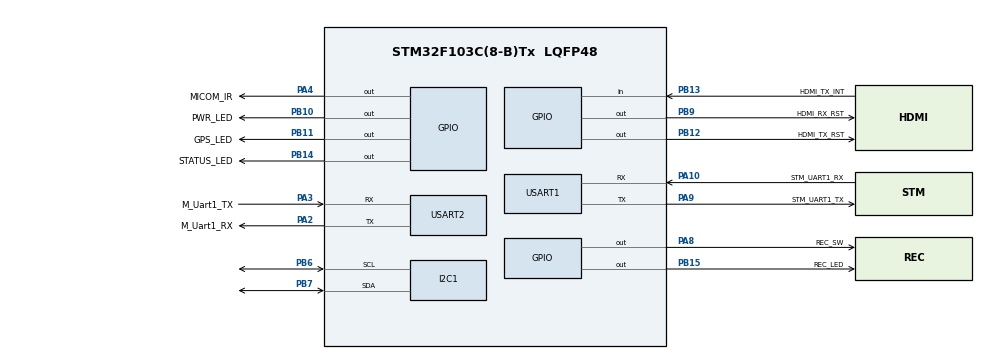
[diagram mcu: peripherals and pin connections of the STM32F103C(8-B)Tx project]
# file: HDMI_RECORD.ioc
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Mcu.Family=STM32F1
Mcu.Name=STM32F103C(8-B)Tx
Mcu.Package=LQFP48
NVIC.PriorityGroup=NVIC_PRIORITYGROUP_4
PA10.GPIO_Label=STM_UART1_RX
PA10.GPIO_PuPd=GPIO_PULLUP
PA10.Mode=Asynchronous
PA10.Signal=USART1_RX
PA2.GPIO_Label=M_Uart1_RX
PA2.Mode=Asynchronous
PA2.Signal=USART2_TX
PA3.GPIO_Label=M_Uart1_TX
PA3.GPIO_PuPd=GPIO_PULLUP
PA3.Mode=Asynchronous
PA3.Signal=USART2_RX
PA4.GPIO_Label=MICOM_IR
PA4.Signal=GPIO_Output
PA8.GPIO_Label=REC_SW
PA8.Signal=GPIO_Output
PA9.GPIO_Label=STM_UART1_TX
PA9.Mode=Asynchronous
PA9.Signal=USART1_TX
PB10.GPIO_Label=PWR_LED
PB10.Signal=GPIO_Output
PB11.GPIO_Label=GPS_LED
PB11.Signal=GPIO_Output
PB12.GPIO_Label=HDMI_TX_RST
PB12.Signal=GPIO_Output
PB13.GPIO_Label=HDMI_TX_INT
PB13.Signal=GPIO_Input
PB14.GPIO_Label=STATUS_LED
PB14.Signal=GPIO_Output
PB15.GPIO_Label=REC_LED
PB15.Signal=GPIO_Output
PB6.Mode=I2C
PB6.Signal=I2C1_SCL
PB7.Mode=I2C
PB7.Signal=I2C1_SDA
PB9.GPIO_Label=HDMI_RX_RST
PB9.Signal=GPIO_Output
ProjectManager.HeapSize=0x200
ProjectManager.StackSize=0x400
ProjectManager.TargetToolchain=STM32CubeIDE
RCC.APB1Freq_Value=8000000
RCC.APB2Freq_Value=8000000
USART1.VirtualMode=VM_ASYNC
USART2.VirtualMode=VM_ASYNC
VP_SYS_VS_ND.Mode=No_Debug
board=custom

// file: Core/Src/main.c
/* USER CODE BEGIN Header */
/**
  ******************************************************************************
  * @file           : main.c
  * @brief          : Main program body
  ******************************************************************************
  * @attention
  *
  * Copyright (c) 2026 STMicroelectronics.
  * All rights reserved.
  *
  * This software is licensed under terms that can be found in the LICENSE file
  * in the root directory of this software component.
  * If no LICENSE file comes with this software, it is provided AS-IS.
  *
  ******************************************************************************
  */
/* USER CODE END Header */
#include "main.h"
#include "stdio.h"
//#include "IT68013CX\it68013CX_main.c" //yjh2026

I2C_HandleTypeDef hi2c1;

UART_HandleTypeDef huart1;
UART_HandleTypeDef huart2;
volatile unsigned int ite_int_check = 0; //oec20251221

void SystemClock_Config(void);
static void MX_GPIO_Init(void);
static void MX_I2C1_Init(void);
static void MX_USART1_UART_Init(void);
static void MX_USART2_UART_Init(void);

/* USER CODE BEGIN 0 */

#if 1	//oec20240609

typedef enum tagHDMI_Video_Type {
    HDMI_Unkown = 0 ,
    HDMI_640x480p60 = 1 ,
    HDMI_480p60,
    HDMI_480p60_16x9,
    HDMI_720p60,
    HDMI_1080i60,
    HDMI_480i60,
    HDMI_480i60_16x9,
    HDMI_1080p60 = 16,
    HDMI_576p50,
    HDMI_576p50_16x9,
    HDMI_720p50,
    HDMI_1080i50,
    HDMI_576i50,
    HDMI_576i50_16x9,
    HDMI_1080p50 = 31,
    HDMI_1080p24,
    HDMI_1080p25,
    HDMI_1080p30,
    HDMI_720p30 = 61,
    HDMI_4k24 =93,
    HDMI_4k25 = 94,
    HDMI_4k30 = 95,
    HDMI_4k24_SMPTE = 98,
} HDMI_Video_Type ;

typedef enum tagHDMI_OutputColorMode {
    HDMI_RGB444,
    HDMI_YUV422,/*20230111*/
    HDMI_YUV444
} HDMI_OutputColorMode ;

typedef unsigned char u8;

#endif

#if 1
int _write(int file, char* p, int len){
	HAL_UART_Transmit(&huart1, (unsigned char*)p, len, 10);
	return len;
}
#endif
void Reset_ITE(void)
{
  printf("#####ITE Reset!!\r\n");
	HAL_Delay(100);
	//yjh2026 회로도 확인해서 수정, PA5(MCU_RESET)은 ITE칩 리셋이 아님
	HAL_GPIO_WritePin(HDMI_RX_RST_GPIO_Port, HDMI_RX_RST_Pin, GPIO_PIN_RESET); //yjh2026 PB9
	HAL_GPIO_WritePin(HDMI_TX_RST_GPIO_Port, HDMI_TX_RST_Pin, GPIO_PIN_RESET); //yjh2026 PB12
	HAL_Delay(100);
	HAL_GPIO_WritePin(HDMI_RX_RST_GPIO_Port, HDMI_RX_RST_Pin, GPIO_PIN_SET); //yjh2026
	HAL_GPIO_WritePin(HDMI_TX_RST_GPIO_Port, HDMI_TX_RST_Pin, GPIO_PIN_SET); //yjh2026
	HAL_Delay(10); //yjh2026 TODO - 리셋후 대기시간 데이터시트 확인
}

void LED_ON_OFF(u8 onoff)
{
	// HAL_GPIO_WritePin(GPIOA, GPIO_PIN_1, onoff);
//  HAL_GPIO_WritePin(GPIOA, UV_LED_ON_Pin, onoff);

	#if 0
	printf("!!!!LED STATUS %d\r\n",onoff);
	printf("!!!!LED STATUS %d\r\n",onoff);
	printf("!!!!LED STATUS %d\r\n",onoff);
	printf("!!!!LED STATUS %d\r\n",onoff);
	#endif
}

void HAL_GPIO_EXTI_Callback(uint16_t GPIO_Pin) {  //oec20251221
	//yjh2026 TODO - .ioc에서 PB13 EXTI로 바꿔야함
	//yjh2026 TODO - RX_INT 미연결이라 RX쪽은 polling으로 처리
	if (GPIO_Pin == HDMI_TX_INT_Pin) { //yjh2026 PB4->PB13 회로도 확인
		if (HAL_GPIO_ReadPin(HDMI_TX_INT_GPIO_Port, HDMI_TX_INT_Pin) == GPIO_PIN_SET) {
			ite_int_check = 1;
			printf("########HDMI TX Interrupt Detected!!\r\n");
		}
	}
}

/* USER CODE END 0 */

int main(void)
{

  /* MCU Configuration--------------------------------------------------------*/

  /* Reset of all peripherals, Initializes the Flash interface and the Systick. */
  HAL_Init();

  /* Configure the system clock */
  SystemClock_Config();

  /* Initialize all configured peripherals */
  MX_GPIO_Init();
  MX_I2C1_Init();
  MX_USART1_UART_Init();
  MX_USART2_UART_Init();

  /* Infinite loop */
  Reset_ITE();

  /* USER CODE BEGIN WHILE */
  while (1)
  {
    extern 	void OEM_1_MainLoop(void);
    extern   void it68013CX_main(void);
	  OEM_1_MainLoop();  //HDMI TX
    it68013CX_main();    //HDMI RX

    /* USER CODE END WHILE */

  }
}

void SystemClock_Config(void)
{
  RCC_OscInitTypeDef RCC_OscInitStruct = {0};
  RCC_ClkInitTypeDef RCC_ClkInitStruct = {0};

  /** Initializes the RCC Oscillators according to the specified parameters
  * in the RCC_OscInitTypeDef structure.
  */
  RCC_OscInitStruct.OscillatorType = RCC_OSCILLATORTYPE_HSI;
  RCC_OscInitStruct.HSIState = RCC_HSI_ON;
  RCC_OscInitStruct.HSICalibrationValue = RCC_HSICALIBRATION_DEFAULT;
  RCC_OscInitStruct.PLL.PLLState = RCC_PLL_NONE;
  if (HAL_RCC_OscConfig(&RCC_OscInitStruct) != HAL_OK)
  {
    Error_Handler();
  }

  /** Initializes the CPU, AHB and APB buses clocks
  */
  RCC_ClkInitStruct.ClockType = RCC_CLOCKTYPE_HCLK|RCC_CLOCKTYPE_SYSCLK
                              |RCC_CLOCKTYPE_PCLK1|RCC_CLOCKTYPE_PCLK2;
  RCC_ClkInitStruct.SYSCLKSource = RCC_SYSCLKSOURCE_HSI;
  RCC_ClkInitStruct.AHBCLKDivider = RCC_SYSCLK_DIV1;
  RCC_ClkInitStruct.APB1CLKDivider = RCC_HCLK_DIV1;
  RCC_ClkInitStruct.APB2CLKDivider = RCC_HCLK_DIV1;

  if (HAL_RCC_ClockConfig(&RCC_ClkInitStruct, FLASH_LATENCY_0) != HAL_OK)
  {
    Error_Handler();
  }
}

static void MX_I2C1_Init(void)
{

  hi2c1.Instance = I2C1;
  hi2c1.Init.ClockSpeed = 100000;
  hi2c1.Init.DutyCycle = I2C_DUTYCYCLE_2;
  hi2c1.Init.OwnAddress1 = 0;
  hi2c1.Init.AddressingMode = I2C_ADDRESSINGMODE_7BIT;
  hi2c1.Init.DualAddressMode = I2C_DUALADDRESS_DISABLE;
  hi2c1.Init.OwnAddress2 = 0;
  hi2c1.Init.GeneralCallMode = I2C_GENERALCALL_DISABLE;
  hi2c1.Init.NoStretchMode = I2C_NOSTRETCH_DISABLE;
  if (HAL_I2C_Init(&hi2c1) != HAL_OK)
  {
    Error_Handler();
  }

}

static void MX_USART1_UART_Init(void)
{

  huart1.Instance = USART1;
  huart1.Init.BaudRate = 115200;
  huart1.Init.WordLength = UART_WORDLENGTH_8B;
  huart1.Init.StopBits = UART_STOPBITS_1;
  huart1.Init.Parity = UART_PARITY_NONE;
  huart1.Init.Mode = UART_MODE_TX_RX;
  huart1.Init.HwFlowCtl = UART_HWCONTROL_NONE;
  huart1.Init.OverSampling = UART_OVERSAMPLING_16;
  if (HAL_UART_Init(&huart1) != HAL_OK)
  {
    Error_Handler();
  }

}

static void MX_USART2_UART_Init(void)
{

  huart2.Instance = USART2;
  huart2.Init.BaudRate = 115200;
  huart2.Init.WordLength = UART_WORDLENGTH_8B;
  huart2.Init.StopBits = UART_STOPBITS_1;
  huart2.Init.Parity = UART_PARITY_NONE;
  huart2.Init.Mode = UART_MODE_TX_RX;
  huart2.Init.HwFlowCtl = UART_HWCONTROL_NONE;
  huart2.Init.OverSampling = UART_OVERSAMPLING_16;
  if (HAL_UART_Init(&huart2) != HAL_OK)
  {
    Error_Handler();
  }

}

static void MX_GPIO_Init(void)
{
  GPIO_InitTypeDef GPIO_InitStruct = {0};

  /* GPIO Ports Clock Enable */
  __HAL_RCC_GPIOA_CLK_ENABLE();
  __HAL_RCC_GPIOB_CLK_ENABLE();

  /*Configure GPIO pin Output Level */
  HAL_GPIO_WritePin(GPIOA, PWR_RST_CTL_Pin|MICOM_IR_Pin|MCU_RESET_Pin|MCU_RESETA7_Pin
                          |REC_SW_Pin, GPIO_PIN_RESET);

  /*Configure GPIO pin Output Level */
  HAL_GPIO_WritePin(GPIOB, PWR_LED_Pin|GPS_LED_Pin|HDMI_TX_RST_Pin|STATUS_LED_Pin
                          |REC_LED_Pin|HDMI_RX_RST_Pin, GPIO_PIN_RESET);

  /*Configure GPIO pins : PWR_RST_CTL_Pin MICOM_IR_Pin MCU_RESET_Pin MCU_RESETA7_Pin
                           REC_SW_Pin */
  GPIO_InitStruct.Pin = PWR_RST_CTL_Pin|MICOM_IR_Pin|MCU_RESET_Pin|MCU_RESETA7_Pin
                          |REC_SW_Pin;
  GPIO_InitStruct.Mode = GPIO_MODE_OUTPUT_PP;
  GPIO_InitStruct.Pull = GPIO_NOPULL;
  GPIO_InitStruct.Speed = GPIO_SPEED_FREQ_LOW;
  HAL_GPIO_Init(GPIOA, &GPIO_InitStruct);

  /*Configure GPIO pins : PWR_LED_Pin GPS_LED_Pin HDMI_TX_RST_Pin STATUS_LED_Pin
                           REC_LED_Pin HDMI_RX_RST_Pin */
  GPIO_InitStruct.Pin = PWR_LED_Pin|GPS_LED_Pin|HDMI_TX_RST_Pin|STATUS_LED_Pin
                          |REC_LED_Pin|HDMI_RX_RST_Pin;
  GPIO_InitStruct.Mode = GPIO_MODE_OUTPUT_PP;
  GPIO_InitStruct.Pull = GPIO_NOPULL;
  GPIO_InitStruct.Speed = GPIO_SPEED_FREQ_LOW;
  HAL_GPIO_Init(GPIOB, &GPIO_InitStruct);

  /*Configure GPIO pin : HDMI_TX_INT_Pin */
  GPIO_InitStruct.Pin = HDMI_TX_INT_Pin;
  GPIO_InitStruct.Mode = GPIO_MODE_INPUT;
  GPIO_InitStruct.Pull = GPIO_NOPULL;
  HAL_GPIO_Init(HDMI_TX_INT_GPIO_Port, &GPIO_InitStruct);

}

void Error_Handler(void)
{
  __disable_irq();
  while (1)
  {
  }
}
